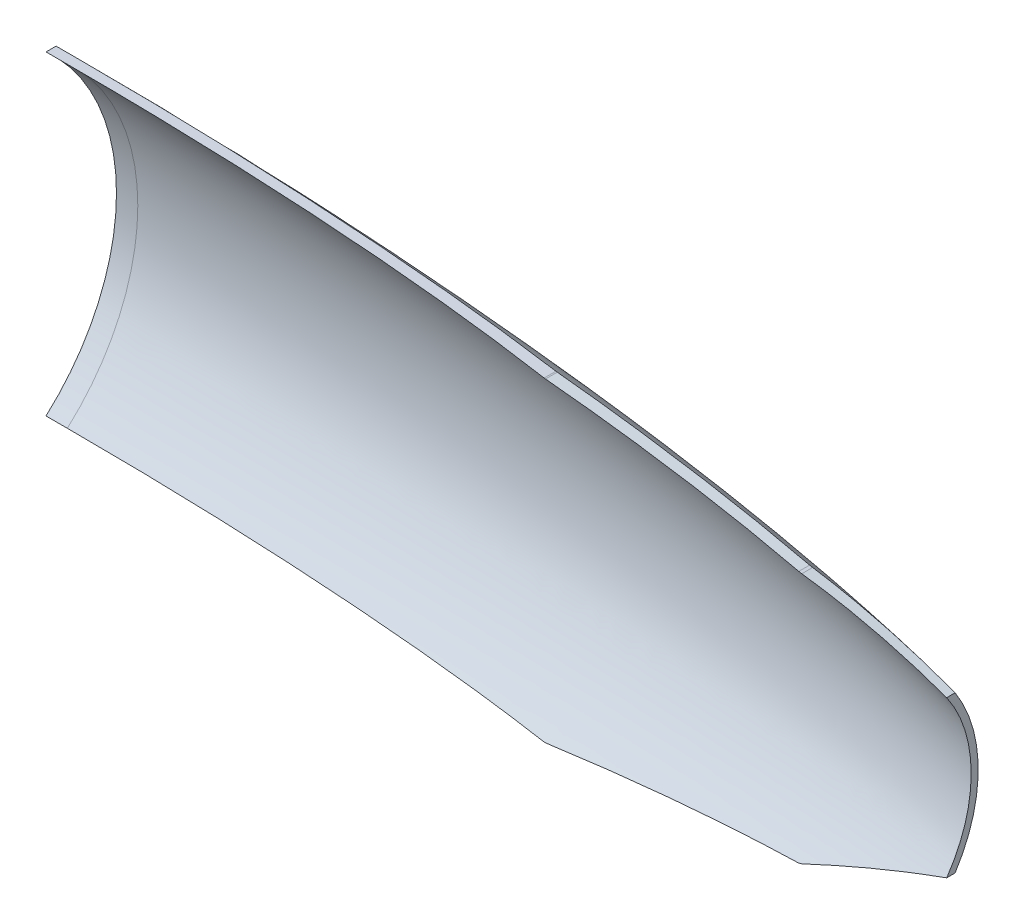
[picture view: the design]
ISO-10303-21;
HEADER;
FILE_DESCRIPTION(('STEP AP214'),'2;1');
FILE_NAME('part.step','',(''),(''),'','','');
FILE_SCHEMA(('AUTOMOTIVE_DESIGN { 1 0 10303 214 1 1 1 1 }'));
ENDSEC;
DATA;
#1=APPLICATION_CONTEXT('core data for automotive mechanical design processes');
#2=APPLICATION_PROTOCOL_DEFINITION('international standard','automotive_design',2000,#1);
#3=PRODUCT_CONTEXT('',#1,'mechanical');
#4=PRODUCT('Part','Part','',(#3));
#5=PRODUCT_RELATED_PRODUCT_CATEGORY('part','',(#4));
#6=PRODUCT_DEFINITION_FORMATION('','',#4);
#7=PRODUCT_DEFINITION_CONTEXT('part definition',#1,'design');
#8=PRODUCT_DEFINITION('design','',#6,#7);
#9=PRODUCT_DEFINITION_SHAPE('','',#8);
#10=(LENGTH_UNIT() NAMED_UNIT(*) SI_UNIT(.MILLI.,.METRE.));
#11=(NAMED_UNIT(*) PLANE_ANGLE_UNIT() SI_UNIT($,.RADIAN.));
#12=(NAMED_UNIT(*) SI_UNIT($,.STERADIAN.) SOLID_ANGLE_UNIT());
#13=UNCERTAINTY_MEASURE_WITH_UNIT(LENGTH_MEASURE(1.E-05),#10,'distance_accuracy_value','');
#14=(GEOMETRIC_REPRESENTATION_CONTEXT(3) GLOBAL_UNCERTAINTY_ASSIGNED_CONTEXT((#13)) GLOBAL_UNIT_ASSIGNED_CONTEXT((#10,
#11,#12)) REPRESENTATION_CONTEXT('',''));
#15=CARTESIAN_POINT('',(0.,0.,0.));
#16=DIRECTION('',(0.,0.,1.));
#17=DIRECTION('',(1.,0.,0.));
#18=AXIS2_PLACEMENT_3D('',#15,#16,#17);
#19=CARTESIAN_POINT('',(0.,0.,0.));
#20=DIRECTION('',(0.,0.,-1.));
#21=DIRECTION('',(1.,0.,0.));
#22=AXIS2_PLACEMENT_3D('',#19,#20,#21);
#23=ELLIPSE('',#22,558.8,101.346);
#24=TRIMMED_CURVE('',#23,(PARAMETER_VALUE(0.)),(PARAMETER_VALUE(3.14159265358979)),.T.,.PARAMETER.);
#25=CARTESIAN_POINT('',(0.,0.,0.));
#26=DIRECTION('',(-1.,0.,0.));
#27=AXIS1_PLACEMENT('',#25,#26);
#28=SURFACE_OF_REVOLUTION('',#24,#27);
#29=CARTESIAN_POINT('',(236.728,73.152,-55.4660351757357));
#30=CARTESIAN_POINT('',(234.412400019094,73.152,-55.7910992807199));
#31=CARTESIAN_POINT('',(232.095758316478,73.152,-56.1087081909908));
#32=CARTESIAN_POINT('',(227.460571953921,73.152,-56.7296548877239));
#33=CARTESIAN_POINT('',(225.14202730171,73.152,-57.0329927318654));
#34=CARTESIAN_POINT('',(220.503655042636,73.152,-57.6259805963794));
#35=CARTESIAN_POINT('',(218.183827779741,73.152,-57.9156333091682));
#36=CARTESIAN_POINT('',(213.54257951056,73.152,-58.481872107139));
#37=CARTESIAN_POINT('',(211.221158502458,73.152,-58.758458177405));
#38=CARTESIAN_POINT('',(204.255226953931,73.152,-59.5693361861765));
#39=CARTESIAN_POINT('',(199.608515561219,73.152,-60.0848157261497));
#40=CARTESIAN_POINT('',(190.31042102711,73.152,-61.0691190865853));
#41=CARTESIAN_POINT('',(185.659038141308,73.152,-61.5379453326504));
#42=CARTESIAN_POINT('',(176.352150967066,73.152,-62.4318897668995));
#43=CARTESIAN_POINT('',(171.696646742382,73.152,-62.8570086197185));
#44=CARTESIAN_POINT('',(162.382035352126,73.152,-63.6660000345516));
#45=CARTESIAN_POINT('',(157.722928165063,73.152,-64.0498723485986));
#46=CARTESIAN_POINT('',(148.408522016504,73.152,-64.7778904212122));
#47=CARTESIAN_POINT('',(143.753227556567,73.152,-65.1220938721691));
#48=CARTESIAN_POINT('',(134.439888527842,73.152,-65.7731646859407));
#49=CARTESIAN_POINT('',(129.781843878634,73.152,-66.0800308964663));
#50=CARTESIAN_POINT('',(120.46341448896,73.152,-66.6578793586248));
#51=CARTESIAN_POINT('',(115.803029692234,73.152,-66.928860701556));
#52=CARTESIAN_POINT('',(106.480317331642,73.152,-67.4361588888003));
#53=CARTESIAN_POINT('',(101.81798974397,73.152,-67.6724752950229));
#54=CARTESIAN_POINT('',(92.4917797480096,73.152,-68.1114620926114));
#55=CARTESIAN_POINT('',(87.8278973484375,73.152,-68.3141326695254));
#56=CARTESIAN_POINT('',(78.4989511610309,73.152,-68.6866720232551));
#57=CARTESIAN_POINT('',(73.8338874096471,73.152,-68.8565417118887));
#58=CARTESIAN_POINT('',(66.2881148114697,73.152,-69.1053097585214));
#59=CARTESIAN_POINT('',(63.4077294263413,73.152,-69.1941448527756));
#60=CARTESIAN_POINT('',(57.6466872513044,73.152,-69.3597080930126));
#61=CARTESIAN_POINT('',(54.7660304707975,73.152,-69.4364365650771));
#62=CARTESIAN_POINT('',(49.0044733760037,73.152,-69.577903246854));
#63=CARTESIAN_POINT('',(46.1235730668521,73.152,-69.6426416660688));
#64=CARTESIAN_POINT('',(40.361554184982,73.152,-69.7602247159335));
#65=CARTESIAN_POINT('',(37.4804356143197,73.152,-69.8130694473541));
#66=CARTESIAN_POINT('',(31.7162714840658,73.152,-69.9069713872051));
#67=CARTESIAN_POINT('',(28.8332258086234,73.152,-69.9480214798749));
#68=CARTESIAN_POINT('',(23.066964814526,73.152,-70.0183512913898));
#69=CARTESIAN_POINT('',(20.1837494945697,73.152,-70.0476309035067));
#70=CARTESIAN_POINT('',(14.4171729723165,73.152,-70.0944628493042));
#71=CARTESIAN_POINT('',(11.533811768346,73.152,-70.1120149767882));
#72=CARTESIAN_POINT('',(5.76696701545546,73.152,-70.1354131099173));
#73=CARTESIAN_POINT('',(2.88348346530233,73.152,-70.1412588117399));
#74=CARTESIAN_POINT('',(0.,73.152,-70.1412618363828));
#75=B_SPLINE_CURVE_WITH_KNOTS('',3,(#29,#30,#31,#32,#33,#34,#35,#36,#37,#38,#39,#40,#41,#42,#43,
#44,#45,#46,#47,#48,#49,#50,#51,#52,#53,#54,#55,#56,#57,#58,#59,#60,#61,#62,#63,#64,#65,#66,#67,
#68,#69,#70,#71,#72,#73,#74),.UNSPECIFIED.,.F.,.F.,(4,2,2,2,2,2,2,2,2,2,2,2,2,2,2,2,2,2,2,2,2,2,
4),(0.,7.01489550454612,14.0297626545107,21.0432439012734,28.0567331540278,42.0821018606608,
56.1067409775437,70.1311667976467,84.1556769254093,98.1595260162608,112.163807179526,
126.168442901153,140.173255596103,154.177991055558,168.182337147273,176.827579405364,
185.472588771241,194.117447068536,202.762232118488,211.41222170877,220.062289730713,
228.712509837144,237.362954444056),.UNSPECIFIED.);
#76=CARTESIAN_POINT('',(236.728,73.1520000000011,-55.4660351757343));
#77=VERTEX_POINT('',#76);
#78=CARTESIAN_POINT('',(0.,73.152,-70.1412618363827));
#79=VERTEX_POINT('',#78);
#80=EDGE_CURVE('E110',#77,#79,#75,.T.);
#81=ORIENTED_EDGE('',*,*,#80,.F.);
#82=CARTESIAN_POINT('',(237.39274838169,73.1171096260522,-55.4185672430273));
#83=CARTESIAN_POINT('',(237.281958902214,73.1229245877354,-55.4265054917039));
#84=CARTESIAN_POINT('',(237.171168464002,73.1287395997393,-55.4344302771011));
#85=CARTESIAN_POINT('',(236.949585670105,73.140369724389,-55.4502529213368));
#86=CARTESIAN_POINT('',(236.838793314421,73.1461848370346,-55.4581507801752));
#87=CARTESIAN_POINT('',(236.728,73.1520000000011,-55.4660351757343));
#88=B_SPLINE_CURVE_WITH_KNOTS('',3,(#82,#83,#84,#85,#86,#87),.UNSPECIFIED.,.F.,.F.,(4,2,4),(0.,
0.333676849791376,0.667353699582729),.UNSPECIFIED.);
#89=CARTESIAN_POINT('',(237.39274838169,73.117109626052,-55.4185672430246));
#90=VERTEX_POINT('',#89);
#91=EDGE_CURVE('E151',#90,#77,#88,.T.);
#92=ORIENTED_EDGE('',*,*,#91,.F.);
#93=CARTESIAN_POINT('',(358.97099166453,58.6193913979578,-50.9530256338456));
#94=CARTESIAN_POINT('',(357.286512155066,58.8202588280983,-51.1122840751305));
#95=CARTESIAN_POINT('',(355.601604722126,59.0211772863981,-51.2669071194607));
#96=CARTESIAN_POINT('',(352.230997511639,59.4231086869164,-51.5671001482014));
#97=CARTESIAN_POINT('',(350.545297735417,59.6241216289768,-51.712670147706));
#98=CARTESIAN_POINT('',(345.488612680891,60.2271110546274,-52.1360010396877));
#99=CARTESIAN_POINT('',(342.116527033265,60.629218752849,-52.4005256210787));
#100=CARTESIAN_POINT('',(335.371053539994,61.4335894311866,-52.8956513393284));
#101=CARTESIAN_POINT('',(331.997666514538,61.8358523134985,-53.1262638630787));
#102=CARTESIAN_POINT('',(325.249659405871,62.6405251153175,-53.5548307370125));
#103=CARTESIAN_POINT('',(321.875039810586,63.0429349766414,-53.7527928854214));
#104=CARTESIAN_POINT('',(315.124633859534,63.8478938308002,-54.1170930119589));
#105=CARTESIAN_POINT('',(311.748847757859,64.2504427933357,-54.2834357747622));
#106=CARTESIAN_POINT('',(304.99615945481,65.0556738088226,-54.5853284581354));
#107=CARTESIAN_POINT('',(301.619257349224,65.4583558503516,-54.7208805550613));
#108=CARTESIAN_POINT('',(294.864550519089,66.2638275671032,-54.9618375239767));
#109=CARTESIAN_POINT('',(291.486745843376,66.6666172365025,-55.0672437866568));
#110=CARTESIAN_POINT('',(284.730037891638,67.4723275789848,-55.248408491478));
#111=CARTESIAN_POINT('',(281.351134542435,67.8752482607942,-55.3241641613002));
#112=CARTESIAN_POINT('',(274.592231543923,68.6812203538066,-55.4463653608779));
#113=CARTESIAN_POINT('',(271.212231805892,69.0842717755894,-55.4928059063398));
#114=CARTESIAN_POINT('',(264.451137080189,69.8905052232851,-55.5565687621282));
#115=CARTESIAN_POINT('',(261.070042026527,70.2936872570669,-55.5738839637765));
#116=CARTESIAN_POINT('',(254.306756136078,71.1001819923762,-55.579458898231));
#117=CARTESIAN_POINT('',(250.924565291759,71.503494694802,-55.5677094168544));
#118=CARTESIAN_POINT('',(244.159087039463,72.3102508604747,-55.5150460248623));
#119=CARTESIAN_POINT('',(240.775799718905,72.7136943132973,-55.4741207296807));
#120=CARTESIAN_POINT('',(237.39274838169,73.117109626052,-55.4185672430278));
#121=B_SPLINE_CURVE_WITH_KNOTS('',3,(#93,#94,#95,#96,#97,#98,#99,#100,#101,#102,#103,#104,#105,
#106,#107,#108,#109,#110,#111,#112,#113,#114,#115,#116,#117,#118,#119,#120),.UNSPECIFIED.,.F.,
.F.,(4,2,2,2,2,2,2,2,2,2,2,2,2,4),(0.,5.11160406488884,10.2231996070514,20.4417947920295,
30.6569509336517,40.8696637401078,51.0808299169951,61.2912741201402,71.501247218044,
81.7121747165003,91.9248378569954,102.139993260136,112.358387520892,122.580771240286),.UNSPECIFIED.);
#122=CARTESIAN_POINT('',(358.97099166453,58.6193913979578,-50.9530256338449));
#123=VERTEX_POINT('',#122);
#124=EDGE_CURVE('E150',#123,#90,#121,.T.);
#125=ORIENTED_EDGE('',*,*,#124,.F.);
#126=CARTESIAN_POINT('',(360.290868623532,58.2986350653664,-51.0145733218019));
#127=CARTESIAN_POINT('',(360.070877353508,58.3520973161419,-51.0045828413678));
#128=CARTESIAN_POINT('',(359.850891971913,58.4055581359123,-50.9944586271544));
#129=CARTESIAN_POINT('',(359.410932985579,58.5124769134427,-50.9739427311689));
#130=CARTESIAN_POINT('',(359.19095938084,58.5659348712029,-50.9635510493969));
#131=CARTESIAN_POINT('',(358.97099166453,58.6193913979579,-50.9530256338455));
#132=B_SPLINE_CURVE_WITH_KNOTS('',3,(#126,#127,#128,#129,#130,#131),.UNSPECIFIED.,.F.,.F.,(4,2,
4),(0.,0.679843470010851,1.35968694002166),.UNSPECIFIED.);
#133=CARTESIAN_POINT('',(360.290868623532,58.2986350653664,-51.0145733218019));
#134=VERTEX_POINT('',#133);
#135=EDGE_CURVE('E155',#134,#123,#132,.T.);
#136=ORIENTED_EDGE('',*,*,#135,.F.);
#137=CARTESIAN_POINT('',(421.64,36.2129477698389,-55.7848384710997));
#138=CARTESIAN_POINT('',(419.925838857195,36.8300457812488,-55.8103963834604));
#139=CARTESIAN_POINT('',(418.21150821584,37.4472048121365,-55.823131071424));
#140=CARTESIAN_POINT('',(414.784668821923,38.6808669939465,-55.822929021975));
#141=CARTESIAN_POINT('',(413.072160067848,39.2973701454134,-55.8100195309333));
#142=CARTESIAN_POINT('',(409.648963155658,40.5297210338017,-55.7585807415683));
#143=CARTESIAN_POINT('',(407.938274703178,41.1455688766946,-55.7200735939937));
#144=CARTESIAN_POINT('',(404.518719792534,42.3766086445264,-55.6173620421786));
#145=CARTESIAN_POINT('',(402.809852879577,42.9918007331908,-55.553174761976));
#146=CARTESIAN_POINT('',(399.393945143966,44.2215275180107,-55.3989237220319));
#147=CARTESIAN_POINT('',(397.686903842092,44.8360623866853,-55.3088719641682));
#148=CARTESIAN_POINT('',(394.274654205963,46.0644722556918,-55.1025990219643));
#149=CARTESIAN_POINT('',(392.569445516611,46.6783473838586,-54.9863844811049));
#150=CARTESIAN_POINT('',(389.160609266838,47.9055284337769,-54.7273549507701));
#151=CARTESIAN_POINT('',(387.456981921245,48.5188342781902,-54.5845367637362));
#152=CARTESIAN_POINT('',(384.051597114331,49.7447728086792,-54.2717729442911));
#153=CARTESIAN_POINT('',(382.349840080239,50.3574053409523,-54.1018220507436));
#154=CARTESIAN_POINT('',(378.94826924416,51.5819708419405,-53.7341195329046));
#155=CARTESIAN_POINT('',(377.248456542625,52.1939034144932,-53.5363563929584));
#156=CARTESIAN_POINT('',(373.850865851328,53.4170360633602,-53.1122001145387));
#157=CARTESIAN_POINT('',(372.153089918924,54.0282353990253,-52.8857883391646));
#158=CARTESIAN_POINT('',(368.759676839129,55.2498641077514,-52.4033453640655));
#159=CARTESIAN_POINT('',(367.064043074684,55.8602922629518,-52.1472872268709));
#160=CARTESIAN_POINT('',(363.675062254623,57.0803253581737,-51.6043152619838));
#161=CARTESIAN_POINT('',(361.98172043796,57.6899284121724,-51.3173645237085));
#162=CARTESIAN_POINT('',(360.290868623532,58.2986350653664,-51.0145733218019));
#163=B_SPLINE_CURVE_WITH_KNOTS('',3,(#137,#138,#139,#140,#141,#142,#143,#144,#145,#146,#147,
#148,#149,#150,#151,#152,#153,#154,#155,#156,#157,#158,#159,#160,#161,#162),.UNSPECIFIED.,.F.,
.F.,(4,2,2,2,2,2,2,2,2,2,2,2,4),(0.,5.46606021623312,10.9263159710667,16.3818528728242,
21.8337579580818,27.2831372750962,32.7311343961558,38.1797867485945,43.6294969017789,
49.0814701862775,54.5370085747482,59.9975434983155,65.4646766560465),.UNSPECIFIED.);
#164=CARTESIAN_POINT('',(421.64,36.2129477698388,-55.7848384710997));
#165=VERTEX_POINT('',#164);
#166=EDGE_CURVE('E159',#165,#134,#163,.T.);
#167=ORIENTED_EDGE('',*,*,#166,.F.);
#168=CARTESIAN_POINT('',(421.64,0.,0.));
#169=DIRECTION('',(-1.,0.,0.));
#170=DIRECTION('',(0.,0.,1.));
#171=AXIS2_PLACEMENT_3D('',#168,#169,#170);
#172=CIRCLE('',#171,66.508088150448);
#173=CARTESIAN_POINT('',(421.64,-36.2129477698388,-55.7848384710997));
#174=VERTEX_POINT('',#173);
#175=EDGE_CURVE('E142',#174,#165,#172,.F.);
#176=ORIENTED_EDGE('',*,*,#175,.F.);
#177=CARTESIAN_POINT('',(360.290868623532,-58.2986350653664,-51.0145733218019));
#178=CARTESIAN_POINT('',(361.98172043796,-57.6899284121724,-51.3173645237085));
#179=CARTESIAN_POINT('',(363.675062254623,-57.0803253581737,-51.6043152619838));
#180=CARTESIAN_POINT('',(367.064043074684,-55.8602922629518,-52.1472872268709));
#181=CARTESIAN_POINT('',(368.759676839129,-55.2498641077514,-52.4033453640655));
#182=CARTESIAN_POINT('',(372.153089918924,-54.0282353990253,-52.8857883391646));
#183=CARTESIAN_POINT('',(373.850865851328,-53.4170360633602,-53.1122001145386));
#184=CARTESIAN_POINT('',(377.248456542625,-52.1939034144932,-53.5363563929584));
#185=CARTESIAN_POINT('',(378.94826924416,-51.5819708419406,-53.7341195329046));
#186=CARTESIAN_POINT('',(382.349840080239,-50.3574053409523,-54.1018220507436));
#187=CARTESIAN_POINT('',(384.051597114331,-49.7447728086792,-54.2717729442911));
#188=CARTESIAN_POINT('',(387.456981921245,-48.5188342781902,-54.5845367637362));
#189=CARTESIAN_POINT('',(389.160609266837,-47.9055284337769,-54.7273549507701));
#190=CARTESIAN_POINT('',(392.569445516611,-46.6783473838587,-54.9863844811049));
#191=CARTESIAN_POINT('',(394.274654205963,-46.0644722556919,-55.1025990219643));
#192=CARTESIAN_POINT('',(397.686903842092,-44.8360623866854,-55.3088719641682));
#193=CARTESIAN_POINT('',(399.393945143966,-44.2215275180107,-55.398923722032));
#194=CARTESIAN_POINT('',(402.809852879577,-42.9918007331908,-55.553174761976));
#195=CARTESIAN_POINT('',(404.518719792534,-42.3766086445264,-55.6173620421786));
#196=CARTESIAN_POINT('',(407.938274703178,-41.1455688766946,-55.7200735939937));
#197=CARTESIAN_POINT('',(409.648963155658,-40.5297210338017,-55.7585807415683));
#198=CARTESIAN_POINT('',(413.072160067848,-39.2973701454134,-55.8100195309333));
#199=CARTESIAN_POINT('',(414.784668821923,-38.6808669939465,-55.822929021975));
#200=CARTESIAN_POINT('',(418.21150821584,-37.4472048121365,-55.823131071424));
#201=CARTESIAN_POINT('',(419.925838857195,-36.8300457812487,-55.8103963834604));
#202=CARTESIAN_POINT('',(421.64,-36.2129477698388,-55.7848384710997));
#203=B_SPLINE_CURVE_WITH_KNOTS('',3,(#177,#178,#179,#180,#181,#182,#183,#184,#185,#186,#187,
#188,#189,#190,#191,#192,#193,#194,#195,#196,#197,#198,#199,#200,#201,#202),.UNSPECIFIED.,.F.,
.F.,(4,2,2,2,2,2,2,2,2,2,2,2,4),(0.,5.46713315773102,10.9276680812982,16.3832064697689,
21.8351797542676,27.284889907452,32.7335422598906,38.1815393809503,43.6309186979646,
49.0828237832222,54.5383606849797,59.9986164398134,65.4646766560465),.UNSPECIFIED.);
#204=CARTESIAN_POINT('',(360.290868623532,-58.2986350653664,-51.0145733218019));
#205=VERTEX_POINT('',#204);
#206=EDGE_CURVE('E164',#205,#174,#203,.T.);
#207=ORIENTED_EDGE('',*,*,#206,.F.);
#208=CARTESIAN_POINT('',(358.97099166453,-58.6193913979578,-50.9530256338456));
#209=CARTESIAN_POINT('',(359.190959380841,-58.5659348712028,-50.9635510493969));
#210=CARTESIAN_POINT('',(359.410932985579,-58.5124769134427,-50.9739427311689));
#211=CARTESIAN_POINT('',(359.850891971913,-58.4055581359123,-50.9944586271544));
#212=CARTESIAN_POINT('',(360.070877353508,-58.3520973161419,-51.0045828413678));
#213=CARTESIAN_POINT('',(360.290868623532,-58.2986350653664,-51.0145733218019));
#214=B_SPLINE_CURVE_WITH_KNOTS('',3,(#208,#209,#210,#211,#212,#213),.UNSPECIFIED.,.F.,.F.,(4,2,
4),(0.,0.679843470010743,1.35968694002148),.UNSPECIFIED.);
#215=CARTESIAN_POINT('',(358.97099166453,-58.6193913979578,-50.9530256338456));
#216=VERTEX_POINT('',#215);
#217=EDGE_CURVE('E168',#216,#205,#214,.T.);
#218=ORIENTED_EDGE('',*,*,#217,.F.);
#219=CARTESIAN_POINT('',(237.39274838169,-73.1171096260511,-55.4185672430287));
#220=CARTESIAN_POINT('',(240.775799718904,-72.7136943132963,-55.474120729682));
#221=CARTESIAN_POINT('',(244.159087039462,-72.3102508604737,-55.5150460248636));
#222=CARTESIAN_POINT('',(250.924565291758,-71.503494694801,-55.5677094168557));
#223=CARTESIAN_POINT('',(254.306756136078,-71.1001819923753,-55.5794588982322));
#224=CARTESIAN_POINT('',(261.070042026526,-70.293687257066,-55.5738839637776));
#225=CARTESIAN_POINT('',(264.451137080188,-69.8905052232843,-55.5565687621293));
#226=CARTESIAN_POINT('',(271.212231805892,-69.0842717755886,-55.4928059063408));
#227=CARTESIAN_POINT('',(274.592231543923,-68.6812203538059,-55.4463653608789));
#228=CARTESIAN_POINT('',(281.351134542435,-67.8752482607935,-55.3241641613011));
#229=CARTESIAN_POINT('',(284.730037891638,-67.4723275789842,-55.2484084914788));
#230=CARTESIAN_POINT('',(291.486745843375,-66.6666172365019,-55.0672437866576));
#231=CARTESIAN_POINT('',(294.864550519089,-66.2638275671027,-54.9618375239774));
#232=CARTESIAN_POINT('',(301.619257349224,-65.4583558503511,-54.7208805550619));
#233=CARTESIAN_POINT('',(304.99615945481,-65.0556738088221,-54.585328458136));
#234=CARTESIAN_POINT('',(311.748847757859,-64.2504427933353,-54.2834357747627));
#235=CARTESIAN_POINT('',(315.124633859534,-63.8478938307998,-54.1170930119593));
#236=CARTESIAN_POINT('',(321.875039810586,-63.0429349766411,-53.7527928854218));
#237=CARTESIAN_POINT('',(325.249659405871,-62.6405251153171,-53.5548307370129));
#238=CARTESIAN_POINT('',(331.997666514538,-61.8358523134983,-53.126263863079));
#239=CARTESIAN_POINT('',(335.371053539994,-61.4335894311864,-52.8956513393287));
#240=CARTESIAN_POINT('',(342.116527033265,-60.6292187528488,-52.4005256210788));
#241=CARTESIAN_POINT('',(345.488612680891,-60.2271110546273,-52.1360010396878));
#242=CARTESIAN_POINT('',(350.545297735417,-59.6241216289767,-51.712670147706));
#243=CARTESIAN_POINT('',(352.230997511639,-59.4231086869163,-51.5671001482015));
#244=CARTESIAN_POINT('',(355.601604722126,-59.021177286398,-51.2669071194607));
#245=CARTESIAN_POINT('',(357.286512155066,-58.8202588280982,-51.1122840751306));
#246=CARTESIAN_POINT('',(358.97099166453,-58.6193913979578,-50.9530256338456));
#247=B_SPLINE_CURVE_WITH_KNOTS('',3,(#219,#220,#221,#222,#223,#224,#225,#226,#227,#228,#229,
#230,#231,#232,#233,#234,#235,#236,#237,#238,#239,#240,#241,#242,#243,#244,#245,#246),
.UNSPECIFIED.,.F.,.F.,(4,2,2,2,2,2,2,2,2,2,2,2,2,4),(0.,10.2223837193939,20.4407779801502,
30.6559333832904,40.8685965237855,51.0795240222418,61.2894971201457,71.4999413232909,
81.7111075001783,91.9238203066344,102.138976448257,112.357571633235,117.469167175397,
122.580771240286),.UNSPECIFIED.);
#248=CARTESIAN_POINT('',(237.39274838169,-73.1171096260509,-55.4185672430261));
#249=VERTEX_POINT('',#248);
#250=EDGE_CURVE('E172',#249,#216,#247,.T.);
#251=ORIENTED_EDGE('',*,*,#250,.F.);
#252=CARTESIAN_POINT('',(236.728,-73.1520000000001,-55.4660351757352));
#253=CARTESIAN_POINT('',(236.838793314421,-73.1461848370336,-55.4581507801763));
#254=CARTESIAN_POINT('',(236.949585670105,-73.140369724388,-55.4502529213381));
#255=CARTESIAN_POINT('',(237.171168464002,-73.1287395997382,-55.4344302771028));
#256=CARTESIAN_POINT('',(237.281958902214,-73.1229245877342,-55.4265054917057));
#257=CARTESIAN_POINT('',(237.39274838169,-73.1171096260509,-55.4185672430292));
#258=B_SPLINE_CURVE_WITH_KNOTS('',3,(#252,#253,#254,#255,#256,#257),.UNSPECIFIED.,.F.,.F.,(4,2,
4),(0.,0.333676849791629,0.667353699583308),.UNSPECIFIED.);
#259=CARTESIAN_POINT('',(236.728,-73.152,-55.4660351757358));
#260=VERTEX_POINT('',#259);
#261=EDGE_CURVE('E82',#260,#249,#258,.T.);
#262=ORIENTED_EDGE('',*,*,#261,.F.);
#263=CARTESIAN_POINT('',(0.,-73.152,-70.1412618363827));
#264=CARTESIAN_POINT('',(5.55624053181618,-73.152,-70.1412197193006));
#265=CARTESIAN_POINT('',(11.1124833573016,-73.152,-70.1195441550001));
#266=CARTESIAN_POINT('',(22.2261068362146,-73.152,-70.0326138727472));
#267=CARTESIAN_POINT('',(27.7834873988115,-73.152,-69.9673475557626));
#268=CARTESIAN_POINT('',(38.8986828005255,-73.152,-69.7929056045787));
#269=CARTESIAN_POINT('',(44.4564975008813,-73.152,-69.6837211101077));
#270=CARTESIAN_POINT('',(55.5718501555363,-73.152,-69.4208160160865));
#271=CARTESIAN_POINT('',(61.1293879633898,-73.152,-69.2670892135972));
#272=CARTESIAN_POINT('',(72.2434704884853,-73.152,-68.9142386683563));
#273=CARTESIAN_POINT('',(77.8000150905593,-73.152,-68.7151112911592));
#274=CARTESIAN_POINT('',(88.911388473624,-73.152,-68.2703180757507));
#275=CARTESIAN_POINT('',(94.4662172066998,-73.152,-68.0246510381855));
#276=CARTESIAN_POINT('',(105.560709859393,-73.152,-67.4859441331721));
#277=CARTESIAN_POINT('',(111.10037914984,-73.152,-67.193015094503));
#278=CARTESIAN_POINT('',(122.176647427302,-73.152,-66.5575816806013));
#279=CARTESIAN_POINT('',(127.713246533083,-73.152,-66.2150793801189));
#280=CARTESIAN_POINT('',(138.782647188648,-73.152,-65.4782765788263));
#281=CARTESIAN_POINT('',(144.315448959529,-73.152,-65.0839794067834));
#282=CARTESIAN_POINT('',(155.376492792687,-73.152,-64.2408592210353));
#283=CARTESIAN_POINT('',(160.904735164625,-73.152,-63.7920402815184));
#284=CARTESIAN_POINT('',(171.955841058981,-73.152,-62.8365263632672));
#285=CARTESIAN_POINT('',(177.47870492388,-73.152,-62.3298353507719));
#286=CARTESIAN_POINT('',(188.518217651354,-73.152,-61.2544550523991));
#287=CARTESIAN_POINT('',(194.034866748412,-73.152,-60.6857681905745));
#288=CARTESIAN_POINT('',(201.099395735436,-73.152,-59.9140130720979));
#289=CARTESIAN_POINT('',(202.6506836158,-73.152,-59.7418537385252));
#290=CARTESIAN_POINT('',(205.75264240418,-73.152,-59.3920784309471));
#291=CARTESIAN_POINT('',(207.303313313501,-73.152,-59.2144624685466));
#292=CARTESIAN_POINT('',(210.403999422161,-73.152,-58.8536363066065));
#293=CARTESIAN_POINT('',(211.954014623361,-73.152,-58.6704261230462));
#294=CARTESIAN_POINT('',(215.053351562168,-73.152,-58.2982616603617));
#295=CARTESIAN_POINT('',(216.602673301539,-73.152,-58.1093073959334));
#296=CARTESIAN_POINT('',(219.701237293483,-73.152,-57.7254143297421));
#297=CARTESIAN_POINT('',(221.250479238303,-73.152,-57.5304730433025));
#298=CARTESIAN_POINT('',(224.348189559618,-73.152,-57.1345102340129));
#299=CARTESIAN_POINT('',(225.896657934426,-73.152,-56.9334886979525));
#300=CARTESIAN_POINT('',(228.992779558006,-73.152,-56.5251823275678));
#301=CARTESIAN_POINT('',(230.540432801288,-73.152,-56.3178974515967));
#302=CARTESIAN_POINT('',(233.634879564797,-73.152,-55.8968636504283));
#303=CARTESIAN_POINT('',(235.181673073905,-73.152,-55.6831146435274));
#304=CARTESIAN_POINT('',(236.728,-73.152,-55.4660351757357));
#305=B_SPLINE_CURVE_WITH_KNOTS('',3,(#263,#264,#265,#266,#267,#268,#269,#270,#271,#272,#273,
#274,#275,#276,#277,#278,#279,#280,#281,#282,#283,#284,#285,#286,#287,#288,#289,#290,#291,#292,
#293,#294,#295,#296,#297,#298,#299,#300,#301,#302,#303,#304),.UNSPECIFIED.,.F.,.F.,(4,2,2,2,2,2,
2,2,2,2,2,2,2,2,2,2,2,2,2,2,4),(0.,16.668683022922,33.3418031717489,50.0182887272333,
66.6970977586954,83.3772424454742,100.057817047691,116.699829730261,133.341146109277,
149.981393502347,166.620398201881,183.258263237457,199.895477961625,204.577906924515,
209.260325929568,213.942731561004,218.625125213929,223.309489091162,227.993863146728,
232.67826835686,237.362732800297),.UNSPECIFIED.);
#306=CARTESIAN_POINT('',(0.,-73.152,-70.1412618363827));
#307=VERTEX_POINT('',#306);
#308=EDGE_CURVE('E123',#307,#260,#305,.T.);
#309=ORIENTED_EDGE('',*,*,#308,.F.);
#310=CARTESIAN_POINT('',(0.,0.,0.));
#311=DIRECTION('',(-1.,0.,0.));
#312=DIRECTION('',(0.,0.,1.));
#313=AXIS2_PLACEMENT_3D('',#310,#311,#312);
#314=CIRCLE('',#313,101.346);
#315=EDGE_CURVE('E127',#79,#307,#314,.T.);
#316=ORIENTED_EDGE('',*,*,#315,.F.);
#317=EDGE_LOOP('',(#81,#92,#125,#136,#167,#176,#207,#218,#251,#262,#309,#316));
#318=FACE_BOUND('',#317,.T.);
#319=ADVANCED_FACE('F38',(#318),#28,.T.);
#320=CARTESIAN_POINT('',(-9.906,0.,0.));
#321=DIRECTION('',(1.,0.,0.));
#322=DIRECTION('',(0.,0.,-1.));
#323=AXIS2_PLACEMENT_3D('',#320,#321,#322);
#324=CYLINDRICAL_SURFACE('',#323,101.346);
#325=DIRECTION('',(1.,0.,0.));
#326=VECTOR('',#325,1.);
#327=CARTESIAN_POINT('',(-9.906,73.152,-70.1412618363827));
#328=LINE('',#327,#326);
#329=CARTESIAN_POINT('',(-9.906,73.152,-70.1412618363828));
#330=VERTEX_POINT('',#329);
#331=EDGE_CURVE('E106',#79,#330,#328,.F.);
#332=ORIENTED_EDGE('',*,*,#331,.F.);
#333=ORIENTED_EDGE('',*,*,#315,.T.);
#334=DIRECTION('',(1.,0.,0.));
#335=VECTOR('',#334,1.);
#336=CARTESIAN_POINT('',(-9.906,-73.152,-70.1412618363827));
#337=LINE('',#336,#335);
#338=CARTESIAN_POINT('',(-9.906,-73.152,-70.1412618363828));
#339=VERTEX_POINT('',#338);
#340=EDGE_CURVE('E12',#339,#307,#337,.T.);
#341=ORIENTED_EDGE('',*,*,#340,.F.);
#342=CARTESIAN_POINT('',(-9.906,0.,0.));
#343=DIRECTION('',(-1.,0.,0.));
#344=DIRECTION('',(0.,0.,1.));
#345=AXIS2_PLACEMENT_3D('',#342,#343,#344);
#346=CIRCLE('',#345,101.346);
#347=EDGE_CURVE('E120',#330,#339,#346,.T.);
#348=ORIENTED_EDGE('',*,*,#347,.F.);
#349=EDGE_LOOP('',(#332,#333,#341,#348));
#350=FACE_BOUND('',#349,.T.);
#351=ADVANCED_FACE('F125',(#350),#324,.T.);
#352=CARTESIAN_POINT('',(-9.906,0.,0.));
#353=DIRECTION('',(-1.,0.,0.));
#354=DIRECTION('',(0.,0.,1.));
#355=AXIS2_PLACEMENT_3D('',#352,#353,#354);
#356=PLANE('',#355);
#357=CARTESIAN_POINT('',(-9.906,0.,0.));
#358=DIRECTION('',(-1.,0.,0.));
#359=DIRECTION('',(0.,0.,1.));
#360=AXIS2_PLACEMENT_3D('',#357,#358,#359);
#361=CIRCLE('',#360,98.171);
#362=CARTESIAN_POINT('',(-9.906,73.152,-65.4700705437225));
#363=VERTEX_POINT('',#362);
#364=CARTESIAN_POINT('',(-9.906,-73.152,-65.4700705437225));
#365=VERTEX_POINT('',#364);
#366=EDGE_CURVE('E122',#363,#365,#361,.T.);
#367=ORIENTED_EDGE('',*,*,#366,.F.);
#368=DIRECTION('',(0.,0.,1.));
#369=VECTOR('',#368,1.);
#370=CARTESIAN_POINT('',(-9.906,73.152,-101.346));
#371=LINE('',#370,#369);
#372=EDGE_CURVE('E103',#330,#363,#371,.T.);
#373=ORIENTED_EDGE('',*,*,#372,.F.);
#374=ORIENTED_EDGE('',*,*,#347,.T.);
#375=DIRECTION('',(0.,0.,1.));
#376=VECTOR('',#375,1.);
#377=CARTESIAN_POINT('',(-9.906,-73.152,-101.346));
#378=LINE('',#377,#376);
#379=EDGE_CURVE('E126',#339,#365,#378,.T.);
#380=ORIENTED_EDGE('',*,*,#379,.T.);
#381=EDGE_LOOP('',(#367,#373,#374,#380));
#382=FACE_BOUND('',#381,.T.);
#383=ADVANCED_FACE('F118',(#382),#356,.T.);
#384=CARTESIAN_POINT('',(0.,0.,0.));
#385=DIRECTION('',(0.,0.,-1.));
#386=DIRECTION('',(1.,0.,0.));
#387=AXIS2_PLACEMENT_3D('',#384,#385,#386);
#388=ELLIPSE('',#387,558.8,101.346);
#389=TRIMMED_CURVE('',#388,(PARAMETER_VALUE(0.)),(PARAMETER_VALUE(3.14159265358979)),.T.,.PARAMETER.);
#390=CARTESIAN_POINT('',(0.,0.,0.));
#391=DIRECTION('',(-1.,0.,0.));
#392=AXIS1_PLACEMENT('',#390,#391);
#393=SURFACE_OF_REVOLUTION('',#389,#392);
#394=OFFSET_SURFACE('',#393,-3.175,.F.);
#395=CARTESIAN_POINT('',(237.39274838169,73.117109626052,-49.9667395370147));
#396=CARTESIAN_POINT('',(237.28195913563,73.122924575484,-49.9749657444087));
#397=CARTESIAN_POINT('',(237.171168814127,73.1287395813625,-49.9831773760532));
#398=CARTESIAN_POINT('',(236.94958602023,73.1403697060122,-49.9995714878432));
#399=CARTESIAN_POINT('',(236.838793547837,73.1461848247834,-50.0077539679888));
#400=CARTESIAN_POINT('',(236.728,73.1520000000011,-50.0159218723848));
#401=B_SPLINE_CURVE_WITH_KNOTS('',3,(#395,#396,#397,#398,#399,#400),.UNSPECIFIED.,.F.,.F.,(4,2,
4),(0.,0.333738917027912,0.667477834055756),.UNSPECIFIED.);
#402=CARTESIAN_POINT('',(237.39274838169,73.117109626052,-49.9667395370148));
#403=VERTEX_POINT('',#402);
#404=CARTESIAN_POINT('',(236.728,73.1520000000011,-50.0159218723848));
#405=VERTEX_POINT('',#404);
#406=EDGE_CURVE('E129',#403,#405,#401,.T.);
#407=ORIENTED_EDGE('',*,*,#406,.T.);
#408=CARTESIAN_POINT('',(236.728,73.152,-50.0159218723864));
#409=CARTESIAN_POINT('',(234.503116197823,73.152,-50.3507222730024));
#410=CARTESIAN_POINT('',(232.277059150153,73.152,-50.6776850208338));
#411=CARTESIAN_POINT('',(227.822815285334,73.152,-51.3166867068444));
#412=CARTESIAN_POINT('',(225.594628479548,73.152,-51.6287257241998));
#413=CARTESIAN_POINT('',(221.136872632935,73.152,-52.2385591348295));
#414=CARTESIAN_POINT('',(218.907304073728,73.152,-52.536357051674));
#415=CARTESIAN_POINT('',(214.446403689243,73.152,-53.1184391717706));
#416=CARTESIAN_POINT('',(212.21507186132,73.152,-53.4027233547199));
#417=CARTESIAN_POINT('',(205.519296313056,73.152,-54.2361297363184));
#418=CARTESIAN_POINT('',(201.052431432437,73.152,-54.7658931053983));
#419=CARTESIAN_POINT('',(192.113636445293,73.152,-55.7778102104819));
#420=CARTESIAN_POINT('',(187.641706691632,73.152,-56.2599670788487));
#421=CARTESIAN_POINT('',(178.693393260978,73.152,-57.1800111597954));
#422=CARTESIAN_POINT('',(174.21700967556,73.152,-57.617899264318));
#423=CARTESIAN_POINT('',(165.260356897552,73.152,-58.4521716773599));
#424=CARTESIAN_POINT('',(160.780087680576,73.152,-58.8485557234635));
#425=CARTESIAN_POINT('',(151.823441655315,73.152,-59.6015106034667));
#426=CARTESIAN_POINT('',(147.347070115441,73.152,-59.9581442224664));
#427=CARTESIAN_POINT('',(138.391353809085,73.152,-60.6342601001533));
#428=CARTESIAN_POINT('',(133.912008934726,73.152,-60.9537409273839));
#429=CARTESIAN_POINT('',(124.950782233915,73.152,-61.5571599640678));
#430=CARTESIAN_POINT('',(120.468900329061,73.152,-61.8410970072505));
#431=CARTESIAN_POINT('',(111.503020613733,73.152,-62.3747792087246));
#432=CARTESIAN_POINT('',(107.019022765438,73.152,-62.6245237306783));
#433=CARTESIAN_POINT('',(98.0493204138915,73.152,-63.0909519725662));
#434=CARTESIAN_POINT('',(93.5636159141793,73.152,-63.3076357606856));
#435=CARTESIAN_POINT('',(84.5908945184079,73.152,-63.7088855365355));
#436=CARTESIAN_POINT('',(80.1038776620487,73.152,-63.8934524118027));
#437=CARTESIAN_POINT('',(72.4681469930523,73.152,-64.1808369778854));
#438=CARTESIAN_POINT('',(69.3197299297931,73.152,-64.2916119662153));
#439=CARTESIAN_POINT('',(63.022500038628,73.152,-64.4979593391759));
#440=CARTESIAN_POINT('',(59.8736872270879,73.152,-64.5935322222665));
#441=CARTESIAN_POINT('',(53.5757087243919,73.152,-64.7696683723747));
#442=CARTESIAN_POINT('',(50.4265430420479,73.152,-64.8502319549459));
#443=CARTESIAN_POINT('',(44.1278986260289,73.152,-64.9965086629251));
#444=CARTESIAN_POINT('',(40.9784198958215,73.152,-65.0622219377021));
#445=CARTESIAN_POINT('',(34.6768486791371,73.152,-65.1789695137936));
#446=CARTESIAN_POINT('',(31.524755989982,73.152,-65.2299928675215));
#447=CARTESIAN_POINT('',(25.2203332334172,73.152,-65.317393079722));
#448=CARTESIAN_POINT('',(22.0680031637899,73.152,-65.3537697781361));
#449=CARTESIAN_POINT('',(15.7631427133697,73.152,-65.4119471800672));
#450=CARTESIAN_POINT('',(12.6106123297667,73.152,-65.4337475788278));
#451=CARTESIAN_POINT('',(6.30538791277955,73.152,-65.4628070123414));
#452=CARTESIAN_POINT('',(3.15269387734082,73.152,-65.470065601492));
#453=CARTESIAN_POINT('',(0.,73.152,-65.4700705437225));
#454=B_SPLINE_CURVE_WITH_KNOTS('',3,(#408,#409,#410,#411,#412,#413,#414,#415,#416,#417,#418,
#419,#420,#421,#422,#423,#424,#425,#426,#427,#428,#429,#430,#431,#432,#433,#434,#435,#436,#437,
#438,#439,#440,#441,#442,#443,#444,#445,#446,#447,#448,#449,#450,#451,#452,#453),.UNSPECIFIED.,
.F.,.F.,(4,2,2,2,2,2,2,2,2,2,2,2,2,2,2,2,2,2,2,2,2,2,4),(0.,6.74977644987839,13.4995170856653,
20.2475789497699,26.9956509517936,40.4898540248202,53.9831686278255,67.4762113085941,
80.9693392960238,94.4408437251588,107.91286702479,121.385332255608,134.85804818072,
148.330736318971,161.803052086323,171.254113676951,180.704865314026,190.155418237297,
199.605876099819,209.063358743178,218.520944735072,227.978728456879,237.436801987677),.UNSPECIFIED.);
#455=CARTESIAN_POINT('',(0.,73.152,-65.4700705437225));
#456=VERTEX_POINT('',#455);
#457=EDGE_CURVE('E138',#405,#456,#454,.T.);
#458=ORIENTED_EDGE('',*,*,#457,.T.);
#459=CARTESIAN_POINT('',(0.,0.,0.));
#460=DIRECTION('',(1.,0.,0.));
#461=DIRECTION('',(0.,0.,-1.));
#462=AXIS2_PLACEMENT_3D('',#459,#460,#461);
#463=CIRCLE('',#462,98.171);
#464=CARTESIAN_POINT('',(0.,-73.152,-65.4700705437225));
#465=VERTEX_POINT('',#464);
#466=EDGE_CURVE('E134',#456,#465,#463,.F.);
#467=ORIENTED_EDGE('',*,*,#466,.T.);
#468=CARTESIAN_POINT('',(0.,-73.152,-65.4700705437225));
#469=CARTESIAN_POINT('',(5.38005689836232,-73.152,-65.4700282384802));
#470=CARTESIAN_POINT('',(10.7601161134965,-73.152,-65.4489170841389));
#471=CARTESIAN_POINT('',(21.5214046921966,-73.152,-65.3642432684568));
#472=CARTESIAN_POINT('',(26.9026339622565,-73.152,-65.3006687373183));
#473=CARTESIAN_POINT('',(37.6655596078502,-73.152,-65.130736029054));
#474=CARTESIAN_POINT('',(43.0472558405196,-73.152,-65.024368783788));
#475=CARTESIAN_POINT('',(53.810404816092,-73.152,-64.7682203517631));
#476=CARTESIAN_POINT('',(59.1918574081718,-73.152,-64.6184328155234));
#477=CARTESIAN_POINT('',(69.953803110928,-73.152,-64.2745774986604));
#478=CARTESIAN_POINT('',(75.3342961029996,-73.152,-64.0805059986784));
#479=CARTESIAN_POINT('',(86.0936001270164,-73.152,-63.646932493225));
#480=CARTESIAN_POINT('',(91.4724111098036,-73.152,-63.407429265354));
#481=CARTESIAN_POINT('',(102.214108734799,-73.152,-62.8821872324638));
#482=CARTESIAN_POINT('',(107.577001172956,-73.152,-62.5965672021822));
#483=CARTESIAN_POINT('',(118.299755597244,-73.152,-61.9768412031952));
#484=CARTESIAN_POINT('',(123.659617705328,-73.152,-61.6427373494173));
#485=CARTESIAN_POINT('',(134.37558600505,-73.152,-60.9237889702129));
#486=CARTESIAN_POINT('',(139.731692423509,-73.152,-60.538947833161));
#487=CARTESIAN_POINT('',(150.439387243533,-73.152,-59.7157483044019));
#488=CARTESIAN_POINT('',(155.790975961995,-73.152,-59.2773940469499));
#489=CARTESIAN_POINT('',(166.488814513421,-73.152,-58.3437424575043));
#490=CARTESIAN_POINT('',(171.835064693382,-73.152,-57.8484491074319));
#491=CARTESIAN_POINT('',(182.521382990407,-73.152,-56.7966836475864));
#492=CARTESIAN_POINT('',(187.861451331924,-73.152,-56.24021383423));
#493=CARTESIAN_POINT('',(195.015252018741,-73.152,-55.4496526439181));
#494=CARTESIAN_POINT('',(196.83225960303,-73.152,-55.2449525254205));
#495=CARTESIAN_POINT('',(200.465356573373,-73.152,-54.8275852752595));
#496=CARTESIAN_POINT('',(202.281445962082,-73.152,-54.6149181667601));
#497=CARTESIAN_POINT('',(205.912633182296,-73.152,-54.1813568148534));
#498=CARTESIAN_POINT('',(207.727731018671,-73.152,-53.9604626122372));
#499=CARTESIAN_POINT('',(211.356861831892,-73.152,-53.5101600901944));
#500=CARTESIAN_POINT('',(213.170894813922,-73.152,-53.2807518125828));
#501=CARTESIAN_POINT('',(216.798835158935,-73.152,-52.8129786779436));
#502=CARTESIAN_POINT('',(218.612741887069,-73.152,-52.574608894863));
#503=CARTESIAN_POINT('',(222.23933297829,-73.152,-52.0886917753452));
#504=CARTESIAN_POINT('',(224.052017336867,-73.152,-51.8411444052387));
#505=CARTESIAN_POINT('',(227.676080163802,-73.152,-51.336500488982));
#506=CARTESIAN_POINT('',(229.487458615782,-73.152,-51.0794038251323));
#507=CARTESIAN_POINT('',(233.10881748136,-73.152,-50.5552419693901));
#508=CARTESIAN_POINT('',(234.918797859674,-73.152,-50.2881765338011));
#509=CARTESIAN_POINT('',(236.728,-73.152,-50.0159218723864));
#510=B_SPLINE_CURVE_WITH_KNOTS('',3,(#468,#469,#470,#471,#472,#473,#474,#475,#476,#477,#478,
#479,#480,#481,#482,#483,#484,#485,#486,#487,#488,#489,#490,#491,#492,#493,#494,#495,#496,#497,
#498,#499,#500,#501,#502,#503,#504,#505,#506,#507,#508,#509),.UNSPECIFIED.,.F.,.F.,(4,2,2,2,2,2,
2,2,2,2,2,2,2,2,2,2,2,2,2,2,4),(0.,16.140133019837,32.284779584,48.4328491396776,
64.5832812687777,80.7350703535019,96.8872940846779,112.998562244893,129.109127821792,
145.218618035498,161.326864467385,177.433985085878,193.540501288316,199.025994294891,
204.511471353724,209.996921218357,215.482344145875,220.970827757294,226.459331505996,
231.947902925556,237.436608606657),.UNSPECIFIED.);
#511=CARTESIAN_POINT('',(236.728,-73.152,-50.0159218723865));
#512=VERTEX_POINT('',#511);
#513=EDGE_CURVE('E137',#465,#512,#510,.T.);
#514=ORIENTED_EDGE('',*,*,#513,.T.);
#515=CARTESIAN_POINT('',(236.728,-73.152,-50.0159218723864));
#516=CARTESIAN_POINT('',(236.838793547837,-73.1461848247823,-50.0077539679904));
#517=CARTESIAN_POINT('',(236.94958602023,-73.1403697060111,-49.9995714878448));
#518=CARTESIAN_POINT('',(237.171168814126,-73.1287395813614,-49.9831773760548));
#519=CARTESIAN_POINT('',(237.28195913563,-73.122924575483,-49.9749657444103));
#520=CARTESIAN_POINT('',(237.39274838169,-73.1171096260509,-49.9667395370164));
#521=B_SPLINE_CURVE_WITH_KNOTS('',3,(#515,#516,#517,#518,#519,#520),.UNSPECIFIED.,.F.,.F.,(4,2,
4),(0.,0.333738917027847,0.667477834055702),.UNSPECIFIED.);
#522=CARTESIAN_POINT('',(237.39274838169,-73.1171096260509,-49.9667395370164));
#523=VERTEX_POINT('',#522);
#524=EDGE_CURVE('E74',#512,#523,#521,.T.);
#525=ORIENTED_EDGE('',*,*,#524,.T.);
#526=CARTESIAN_POINT('',(237.39274838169,-73.1171096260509,-49.9667395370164));
#527=CARTESIAN_POINT('',(240.775495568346,-72.7137305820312,-50.0459976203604));
#528=CARTESIAN_POINT('',(244.158606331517,-72.3103081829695,-50.1094084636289));
#529=CARTESIAN_POINT('',(250.923759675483,-71.503590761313,-50.2047467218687));
#530=CARTESIAN_POINT('',(254.30580206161,-71.1002957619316,-50.2366881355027));
#531=CARTESIAN_POINT('',(261.068818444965,-70.2938331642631,-50.2693628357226));
#532=CARTESIAN_POINT('',(264.449792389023,-69.8906655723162,-50.2701073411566));
#533=CARTESIAN_POINT('',(271.210673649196,-69.0844575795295,-50.2404459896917));
#534=CARTESIAN_POINT('',(274.590581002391,-68.6814171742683,-50.2100487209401));
#535=CARTESIAN_POINT('',(281.349329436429,-67.8754635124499,-50.1180025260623));
#536=CARTESIAN_POINT('',(284.728170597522,-67.4725502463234,-50.0563595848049));
#537=CARTESIAN_POINT('',(291.484786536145,-66.6668508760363,-49.9015434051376));
#538=CARTESIAN_POINT('',(294.862561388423,-66.2640647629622,-49.8083734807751));
#539=CARTESIAN_POINT('',(301.617258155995,-65.4585942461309,-49.5900364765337));
#540=CARTESIAN_POINT('',(304.994180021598,-65.0559098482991,-49.4648678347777));
#541=CARTESIAN_POINT('',(311.746951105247,-64.2506689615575,-49.1818803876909));
#542=CARTESIAN_POINT('',(315.122800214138,-63.848112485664,-49.0240589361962));
#543=CARTESIAN_POINT('',(321.873374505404,-63.0431335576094,-48.6748969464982));
#544=CARTESIAN_POINT('',(325.248099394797,-62.6407111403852,-48.4835506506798));
#545=CARTESIAN_POINT('',(331.996356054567,-61.8360085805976,-48.0662288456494));
#546=CARTESIAN_POINT('',(335.369887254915,-61.4337285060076,-47.8402439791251));
#547=CARTESIAN_POINT('',(342.115683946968,-60.6293192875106,-47.3522586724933));
#548=CARTESIAN_POINT('',(345.487948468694,-60.2271902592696,-47.0902445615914));
#549=CARTESIAN_POINT('',(350.544869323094,-59.6241727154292,-46.6689569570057));
#550=CARTESIAN_POINT('',(352.230691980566,-59.4231451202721,-46.5237761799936));
#551=CARTESIAN_POINT('',(355.601493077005,-59.0211905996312,-46.2237586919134));
#552=CARTESIAN_POINT('',(357.286471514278,-58.8202636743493,-46.0689219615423));
#553=CARTESIAN_POINT('',(358.97099166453,-58.6193913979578,-45.9091335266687));
#554=B_SPLINE_CURVE_WITH_KNOTS('',3,(#526,#527,#528,#529,#530,#531,#532,#533,#534,#535,#536,
#537,#538,#539,#540,#541,#542,#543,#544,#545,#546,#547,#548,#549,#550,#551,#552,#553),
.UNSPECIFIED.,.F.,.F.,(4,2,2,2,2,2,2,2,2,2,2,2,2,4),(0.,10.2228637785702,20.4411780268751,
30.6558175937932,40.867640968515,51.0775090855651,61.2863042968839,71.49559790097,
81.705719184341,91.9175956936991,102.132235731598,112.350762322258,117.462625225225,
122.574498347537),.UNSPECIFIED.);
#555=CARTESIAN_POINT('',(358.97099166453,-58.6193913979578,-45.9091335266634));
#556=VERTEX_POINT('',#555);
#557=EDGE_CURVE('E259',#523,#556,#554,.T.);
#558=ORIENTED_EDGE('',*,*,#557,.T.);
#559=CARTESIAN_POINT('',(358.97099166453,-58.6193913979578,-45.9091335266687));
#560=CARTESIAN_POINT('',(359.190953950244,-58.5659361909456,-45.9230310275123));
#561=CARTESIAN_POINT('',(359.410924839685,-58.5124788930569,-45.9367811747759));
#562=CARTESIAN_POINT('',(359.850883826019,-58.4055601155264,-45.9639867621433));
#563=CARTESIAN_POINT('',(360.070871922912,-58.3520986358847,-45.977442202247));
#564=CARTESIAN_POINT('',(360.290868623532,-58.2986350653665,-45.9907502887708));
#565=B_SPLINE_CURVE_WITH_KNOTS('',3,(#559,#560,#561,#562,#563,#564),.UNSPECIFIED.,.F.,.F.,(4,2,
4),(0.,0.680371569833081,1.36074313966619),.UNSPECIFIED.);
#566=CARTESIAN_POINT('',(360.290868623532,-58.2986350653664,-45.990750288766));
#567=VERTEX_POINT('',#566);
#568=EDGE_CURVE('E252',#556,#567,#565,.T.);
#569=ORIENTED_EDGE('',*,*,#568,.T.);
#570=CARTESIAN_POINT('',(360.290868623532,-58.2986350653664,-45.9907502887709));
#571=CARTESIAN_POINT('',(361.133896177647,-57.9951451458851,-46.1667539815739));
#572=CARTESIAN_POINT('',(361.977756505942,-57.6913554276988,-46.3382111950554));
#573=CARTESIAN_POINT('',(363.667025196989,-57.0832186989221,-46.6722534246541));
#574=CARTESIAN_POINT('',(364.512433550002,-56.7788716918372,-46.8348384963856));
#575=CARTESIAN_POINT('',(367.048311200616,-55.8659557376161,-47.3091505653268));
#576=CARTESIAN_POINT('',(368.740933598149,-55.2566116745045,-47.6079549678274));
#577=CARTESIAN_POINT('',(372.129162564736,-54.0368492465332,-48.1722574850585));
#578=CARTESIAN_POINT('',(373.82476382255,-53.4264327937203,-48.4377917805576));
#579=CARTESIAN_POINT('',(377.218777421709,-52.2045878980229,-48.9370138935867));
#580=CARTESIAN_POINT('',(378.917186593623,-51.593160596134,-49.1707260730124));
#581=CARTESIAN_POINT('',(382.31665607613,-50.3693515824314,-49.6075082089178));
#582=CARTESIAN_POINT('',(384.017714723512,-49.756970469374,-49.8105928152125));
#583=CARTESIAN_POINT('',(387.422356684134,-48.5312993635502,-50.187107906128));
#584=CARTESIAN_POINT('',(389.125939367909,-47.9180095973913,-50.3605448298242));
#585=CARTESIAN_POINT('',(392.535150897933,-46.6906934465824,-50.6785292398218));
#586=CARTESIAN_POINT('',(394.240779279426,-46.0766672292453,-50.8230823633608));
#587=CARTESIAN_POINT('',(397.654479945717,-44.8477349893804,-51.0839870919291));
#588=CARTESIAN_POINT('',(399.362552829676,-44.2328287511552,-51.2003298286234));
#589=CARTESIAN_POINT('',(402.781125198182,-43.0021426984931,-51.4052932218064));
#590=CARTESIAN_POINT('',(404.491625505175,-42.3863625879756,-51.4938983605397));
#591=CARTESIAN_POINT('',(407.91504113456,-41.1539329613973,-51.6437214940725));
#592=CARTESIAN_POINT('',(409.627957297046,-40.5372831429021,-51.7049177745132));
#593=CARTESIAN_POINT('',(413.056197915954,-39.3031165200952,-51.8001317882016));
#594=CARTESIAN_POINT('',(414.77152305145,-38.685599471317,-51.8341218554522));
#595=CARTESIAN_POINT('',(418.204581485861,-37.4496984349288,-51.8749764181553));
#596=CARTESIAN_POINT('',(419.922315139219,-36.8313143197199,-51.8818073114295));
#597=CARTESIAN_POINT('',(421.64,-36.2129477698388,-51.8750951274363));
#598=B_SPLINE_CURVE_WITH_KNOTS('',3,(#570,#571,#572,#573,#574,#575,#576,#577,#578,#579,#580,
#581,#582,#583,#584,#585,#586,#587,#588,#589,#590,#591,#592,#593,#594,#595,#596,#597),
.UNSPECIFIED.,.F.,.F.,(4,2,2,2,2,2,2,2,2,2,2,2,2,4),(0.,2.73931878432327,5.47862039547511,
10.9491006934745,16.4135793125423,21.873850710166,27.3315020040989,32.7879664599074,
38.2433649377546,43.7004761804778,49.1606349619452,54.6251118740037,60.0951385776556,
65.5719308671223),.UNSPECIFIED.);
#599=CARTESIAN_POINT('',(421.64,-36.2129477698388,-51.8750951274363));
#600=VERTEX_POINT('',#599);
#601=EDGE_CURVE('E245',#567,#600,#598,.T.);
#602=ORIENTED_EDGE('',*,*,#601,.T.);
#603=CARTESIAN_POINT('',(421.64,0.,0.));
#604=DIRECTION('',(-1.,0.,0.));
#605=DIRECTION('',(0.,0.,1.));
#606=AXIS2_PLACEMENT_3D('',#603,#604,#605);
#607=CIRCLE('',#606,63.2645483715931);
#608=CARTESIAN_POINT('',(421.64,36.2129477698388,-51.8750951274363));
#609=VERTEX_POINT('',#608);
#610=EDGE_CURVE('E207',#600,#609,#607,.F.);
#611=ORIENTED_EDGE('',*,*,#610,.T.);
#612=CARTESIAN_POINT('',(421.64,36.2129477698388,-51.8750951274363));
#613=CARTESIAN_POINT('',(419.922315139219,36.83131431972,-51.8818073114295));
#614=CARTESIAN_POINT('',(418.204581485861,37.4496984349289,-51.8749764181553));
#615=CARTESIAN_POINT('',(414.77152305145,38.685599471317,-51.8341218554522));
#616=CARTESIAN_POINT('',(413.056197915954,39.3031165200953,-51.8001317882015));
#617=CARTESIAN_POINT('',(409.627957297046,40.5372831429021,-51.7049177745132));
#618=CARTESIAN_POINT('',(407.91504113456,41.1539329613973,-51.6437214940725));
#619=CARTESIAN_POINT('',(404.491625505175,42.3863625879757,-51.4938983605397));
#620=CARTESIAN_POINT('',(402.781125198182,43.0021426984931,-51.4052932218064));
#621=CARTESIAN_POINT('',(399.362552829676,44.2328287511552,-51.2003298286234));
#622=CARTESIAN_POINT('',(397.654479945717,44.8477349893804,-51.0839870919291));
#623=CARTESIAN_POINT('',(394.240779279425,46.0766672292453,-50.8230823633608));
#624=CARTESIAN_POINT('',(392.535150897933,46.6906934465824,-50.6785292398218));
#625=CARTESIAN_POINT('',(389.125939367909,47.9180095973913,-50.3605448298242));
#626=CARTESIAN_POINT('',(387.422356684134,48.5312993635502,-50.187107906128));
#627=CARTESIAN_POINT('',(384.017714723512,49.756970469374,-49.8105928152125));
#628=CARTESIAN_POINT('',(382.31665607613,50.3693515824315,-49.6075082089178));
#629=CARTESIAN_POINT('',(378.917186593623,51.593160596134,-49.1707260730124));
#630=CARTESIAN_POINT('',(377.218777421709,52.2045878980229,-48.9370138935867));
#631=CARTESIAN_POINT('',(373.824763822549,53.4264327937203,-48.4377917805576));
#632=CARTESIAN_POINT('',(372.129162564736,54.0368492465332,-48.1722574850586));
#633=CARTESIAN_POINT('',(368.740933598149,55.2566116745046,-47.6079549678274));
#634=CARTESIAN_POINT('',(367.048311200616,55.8659557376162,-47.3091505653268));
#635=CARTESIAN_POINT('',(364.512433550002,56.7788716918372,-46.8348384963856));
#636=CARTESIAN_POINT('',(363.667025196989,57.0832186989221,-46.6722534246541));
#637=CARTESIAN_POINT('',(361.977756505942,57.6913554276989,-46.3382111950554));
#638=CARTESIAN_POINT('',(361.133896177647,57.9951451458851,-46.1667539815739));
#639=CARTESIAN_POINT('',(360.290868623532,58.2986350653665,-45.9907502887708));
#640=B_SPLINE_CURVE_WITH_KNOTS('',3,(#612,#613,#614,#615,#616,#617,#618,#619,#620,#621,#622,
#623,#624,#625,#626,#627,#628,#629,#630,#631,#632,#633,#634,#635,#636,#637,#638,#639),
.UNSPECIFIED.,.F.,.F.,(4,2,2,2,2,2,2,2,2,2,2,2,2,4),(0.,5.4767922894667,10.9468189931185,
16.4112959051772,21.8714546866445,27.3285659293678,32.783964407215,38.2404288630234,
43.6980801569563,49.1583515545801,54.6228301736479,60.0933104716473,62.8326120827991,
65.5719308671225),.UNSPECIFIED.);
#641=CARTESIAN_POINT('',(360.290868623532,58.2986350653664,-45.990750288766));
#642=VERTEX_POINT('',#641);
#643=EDGE_CURVE('E238',#609,#642,#640,.T.);
#644=ORIENTED_EDGE('',*,*,#643,.T.);
#645=CARTESIAN_POINT('',(360.290868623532,58.2986350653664,-45.9907502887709));
#646=CARTESIAN_POINT('',(360.070871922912,58.3520986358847,-45.977442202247));
#647=CARTESIAN_POINT('',(359.850883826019,58.4055601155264,-45.9639867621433));
#648=CARTESIAN_POINT('',(359.410924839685,58.5124788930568,-45.9367811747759));
#649=CARTESIAN_POINT('',(359.190953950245,58.5659361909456,-45.9230310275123));
#650=CARTESIAN_POINT('',(358.97099166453,58.6193913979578,-45.9091335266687));
#651=B_SPLINE_CURVE_WITH_KNOTS('',3,(#645,#646,#647,#648,#649,#650),.UNSPECIFIED.,.F.,.F.,(4,2,
4),(0.,0.680371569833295,1.36074313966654),.UNSPECIFIED.);
#652=CARTESIAN_POINT('',(358.97099166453,58.6193913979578,-45.9091335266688));
#653=VERTEX_POINT('',#652);
#654=EDGE_CURVE('E231',#642,#653,#651,.T.);
#655=ORIENTED_EDGE('',*,*,#654,.T.);
#656=CARTESIAN_POINT('',(358.97099166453,58.6193913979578,-45.9091335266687));
#657=CARTESIAN_POINT('',(357.286471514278,58.8202636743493,-46.0689219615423));
#658=CARTESIAN_POINT('',(355.601493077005,59.0211905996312,-46.2237586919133));
#659=CARTESIAN_POINT('',(352.230691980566,59.4231451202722,-46.5237761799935));
#660=CARTESIAN_POINT('',(350.544869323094,59.6241727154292,-46.6689569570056));
#661=CARTESIAN_POINT('',(345.487948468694,60.2271902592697,-47.0902445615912));
#662=CARTESIAN_POINT('',(342.115683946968,60.6293192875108,-47.3522586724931));
#663=CARTESIAN_POINT('',(335.369887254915,61.4337285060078,-47.8402439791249));
#664=CARTESIAN_POINT('',(331.996356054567,61.8360085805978,-48.0662288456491));
#665=CARTESIAN_POINT('',(325.248099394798,62.6407111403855,-48.4835506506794));
#666=CARTESIAN_POINT('',(321.873374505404,63.0431335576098,-48.6748969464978));
#667=CARTESIAN_POINT('',(315.122800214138,63.8481124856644,-49.0240589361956));
#668=CARTESIAN_POINT('',(311.746951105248,64.2506689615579,-49.1818803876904));
#669=CARTESIAN_POINT('',(304.994180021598,65.0559098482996,-49.4648678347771));
#670=CARTESIAN_POINT('',(301.617258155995,65.4585942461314,-49.590036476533));
#671=CARTESIAN_POINT('',(294.862561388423,66.2640647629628,-49.8083734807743));
#672=CARTESIAN_POINT('',(291.484786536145,66.6668508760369,-49.9015434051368));
#673=CARTESIAN_POINT('',(284.728170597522,67.472550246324,-50.056359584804));
#674=CARTESIAN_POINT('',(281.349329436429,67.8754635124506,-50.1180025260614));
#675=CARTESIAN_POINT('',(274.590581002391,68.681417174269,-50.2100487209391));
#676=CARTESIAN_POINT('',(271.210673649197,69.0844575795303,-50.2404459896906));
#677=CARTESIAN_POINT('',(264.449792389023,69.890665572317,-50.2701073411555));
#678=CARTESIAN_POINT('',(261.068818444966,70.2938331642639,-50.2693628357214));
#679=CARTESIAN_POINT('',(254.30580206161,71.1002957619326,-50.2366881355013));
#680=CARTESIAN_POINT('',(250.923759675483,71.503590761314,-50.2047467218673));
#681=CARTESIAN_POINT('',(244.158606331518,72.3103081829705,-50.1094084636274));
#682=CARTESIAN_POINT('',(240.775495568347,72.7137305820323,-50.0459976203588));
#683=CARTESIAN_POINT('',(237.39274838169,73.117109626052,-49.9667395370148));
#684=B_SPLINE_CURVE_WITH_KNOTS('',3,(#656,#657,#658,#659,#660,#661,#662,#663,#664,#665,#666,
#667,#668,#669,#670,#671,#672,#673,#674,#675,#676,#677,#678,#679,#680,#681,#682,#683),
.UNSPECIFIED.,.F.,.F.,(4,2,2,2,2,2,2,2,2,2,2,2,2,4),(0.,5.11187312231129,10.2237360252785,
20.4422626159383,30.6569026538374,40.8687791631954,51.0789004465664,61.2881940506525,
71.4969892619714,81.7068573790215,91.9186807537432,102.133320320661,112.351634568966,
122.574498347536),.UNSPECIFIED.);
#685=EDGE_CURVE('E224',#653,#403,#684,.T.);
#686=ORIENTED_EDGE('',*,*,#685,.T.);
#687=EDGE_LOOP('',(#407,#458,#467,#514,#525,#558,#569,#602,#611,#644,#655,#686));
#688=FACE_BOUND('',#687,.T.);
#689=ADVANCED_FACE('F208',(#688),#394,.F.);
#690=CARTESIAN_POINT('',(-9.906,0.,0.));
#691=DIRECTION('',(1.,0.,0.));
#692=DIRECTION('',(0.,0.,-1.));
#693=AXIS2_PLACEMENT_3D('',#690,#691,#692);
#694=CYLINDRICAL_SURFACE('',#693,98.171);
#695=ORIENTED_EDGE('',*,*,#466,.F.);
#696=DIRECTION('',(1.,0.,0.));
#697=VECTOR('',#696,1.);
#698=CARTESIAN_POINT('',(-9.906,73.152,-65.4700705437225));
#699=LINE('',#698,#697);
#700=EDGE_CURVE('E141',#456,#363,#699,.F.);
#701=ORIENTED_EDGE('',*,*,#700,.T.);
#702=ORIENTED_EDGE('',*,*,#366,.T.);
#703=DIRECTION('',(1.,0.,0.));
#704=VECTOR('',#703,1.);
#705=CARTESIAN_POINT('',(-9.906,-73.152,-65.4700705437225));
#706=LINE('',#705,#704);
#707=EDGE_CURVE('E140',#365,#465,#706,.T.);
#708=ORIENTED_EDGE('',*,*,#707,.T.);
#709=EDGE_LOOP('',(#695,#701,#702,#708));
#710=FACE_BOUND('',#709,.T.);
#711=ADVANCED_FACE('F213',(#710),#694,.F.);
#712=CARTESIAN_POINT('',(236.728,73.1520000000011,-101.346));
#713=DIRECTION('',(0.0524144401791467,0.998625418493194,0.));
#714=DIRECTION('',(-0.998625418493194,0.0524144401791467,0.));
#715=AXIS2_PLACEMENT_3D('',#712,#713,#714);
#716=PLANE('',#715);
#717=ORIENTED_EDGE('',*,*,#91,.T.);
#718=DIRECTION('',(0.,0.,1.));
#719=VECTOR('',#718,1.);
#720=CARTESIAN_POINT('',(236.728,73.1520000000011,-101.346));
#721=LINE('',#720,#719);
#722=EDGE_CURVE('E147',#77,#405,#721,.T.);
#723=ORIENTED_EDGE('',*,*,#722,.T.);
#724=ORIENTED_EDGE('',*,*,#406,.F.);
#725=DIRECTION('',(0.,0.,1.));
#726=VECTOR('',#725,1.);
#727=CARTESIAN_POINT('',(237.39274838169,73.117109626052,-101.346));
#728=LINE('',#727,#726);
#729=EDGE_CURVE('E152',#90,#403,#728,.T.);
#730=ORIENTED_EDGE('',*,*,#729,.F.);
#731=EDGE_LOOP('',(#717,#723,#724,#730));
#732=FACE_BOUND('',#731,.T.);
#733=ADVANCED_FACE('F279',(#732),#716,.T.);
#734=CARTESIAN_POINT('',(237.39274838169,73.117109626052,-101.346));
#735=DIRECTION('',(0.118407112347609,0.992965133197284,0.));
#736=DIRECTION('',(-0.992965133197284,0.118407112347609,0.));
#737=AXIS2_PLACEMENT_3D('',#734,#735,#736);
#738=PLANE('',#737);
#739=ORIENTED_EDGE('',*,*,#124,.T.);
#740=ORIENTED_EDGE('',*,*,#729,.T.);
#741=ORIENTED_EDGE('',*,*,#685,.F.);
#742=DIRECTION('',(0.,0.,1.));
#743=VECTOR('',#742,1.);
#744=CARTESIAN_POINT('',(358.97099166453,58.6193913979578,-101.346));
#745=LINE('',#744,#743);
#746=EDGE_CURVE('E156',#123,#653,#745,.T.);
#747=ORIENTED_EDGE('',*,*,#746,.F.);
#748=EDGE_LOOP('',(#739,#740,#741,#747));
#749=FACE_BOUND('',#748,.T.);
#750=ADVANCED_FACE('F282',(#749),#738,.T.);
#751=CARTESIAN_POINT('',(358.97099166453,58.6193913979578,-101.346));
#752=DIRECTION('',(0.236146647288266,0.971717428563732,0.));
#753=DIRECTION('',(-0.971717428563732,0.236146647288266,0.));
#754=AXIS2_PLACEMENT_3D('',#751,#752,#753);
#755=PLANE('',#754);
#756=ORIENTED_EDGE('',*,*,#135,.T.);
#757=ORIENTED_EDGE('',*,*,#746,.T.);
#758=ORIENTED_EDGE('',*,*,#654,.F.);
#759=DIRECTION('',(0.,0.,1.));
#760=VECTOR('',#759,1.);
#761=CARTESIAN_POINT('',(360.290868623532,58.2986350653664,-101.346));
#762=LINE('',#761,#760);
#763=EDGE_CURVE('E145',#134,#642,#762,.T.);
#764=ORIENTED_EDGE('',*,*,#763,.F.);
#765=EDGE_LOOP('',(#756,#757,#758,#764));
#766=FACE_BOUND('',#765,.T.);
#767=ADVANCED_FACE('F339',(#766),#755,.T.);
#768=CARTESIAN_POINT('',(421.64,36.2129477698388,-101.346));
#769=DIRECTION('',(0.338719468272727,0.940887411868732,0.));
#770=DIRECTION('',(-0.940887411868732,0.338719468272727,0.));
#771=AXIS2_PLACEMENT_3D('',#768,#769,#770);
#772=PLANE('',#771);
#773=ORIENTED_EDGE('',*,*,#166,.T.);
#774=ORIENTED_EDGE('',*,*,#763,.T.);
#775=ORIENTED_EDGE('',*,*,#643,.F.);
#776=DIRECTION('',(0.,0.,1.));
#777=VECTOR('',#776,1.);
#778=CARTESIAN_POINT('',(421.64,36.2129477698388,-101.346));
#779=LINE('',#778,#777);
#780=EDGE_CURVE('E144',#165,#609,#779,.T.);
#781=ORIENTED_EDGE('',*,*,#780,.F.);
#782=EDGE_LOOP('',(#773,#774,#775,#781));
#783=FACE_BOUND('',#782,.T.);
#784=ADVANCED_FACE('F336',(#783),#772,.T.);
#785=CARTESIAN_POINT('',(421.64,-36.2129477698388,-101.346));
#786=DIRECTION('',(1.,0.,0.));
#787=DIRECTION('',(0.,0.,-1.));
#788=AXIS2_PLACEMENT_3D('',#785,#786,#787);
#789=PLANE('',#788);
#790=ORIENTED_EDGE('',*,*,#175,.T.);
#791=ORIENTED_EDGE('',*,*,#780,.T.);
#792=ORIENTED_EDGE('',*,*,#610,.F.);
#793=DIRECTION('',(0.,0.,1.));
#794=VECTOR('',#793,1.);
#795=CARTESIAN_POINT('',(421.64,-36.2129477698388,-101.346));
#796=LINE('',#795,#794);
#797=EDGE_CURVE('E165',#174,#600,#796,.T.);
#798=ORIENTED_EDGE('',*,*,#797,.F.);
#799=EDGE_LOOP('',(#790,#791,#792,#798));
#800=FACE_BOUND('',#799,.T.);
#801=ADVANCED_FACE('F321',(#800),#789,.T.);
#802=CARTESIAN_POINT('',(421.64,-36.2129477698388,-101.346));
#803=DIRECTION('',(0.338719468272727,-0.940887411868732,0.));
#804=DIRECTION('',(0.940887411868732,0.338719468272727,0.));
#805=AXIS2_PLACEMENT_3D('',#802,#803,#804);
#806=PLANE('',#805);
#807=ORIENTED_EDGE('',*,*,#206,.T.);
#808=ORIENTED_EDGE('',*,*,#797,.T.);
#809=ORIENTED_EDGE('',*,*,#601,.F.);
#810=DIRECTION('',(0.,0.,1.));
#811=VECTOR('',#810,1.);
#812=CARTESIAN_POINT('',(360.290868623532,-58.2986350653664,-101.346));
#813=LINE('',#812,#811);
#814=EDGE_CURVE('E169',#205,#567,#813,.T.);
#815=ORIENTED_EDGE('',*,*,#814,.F.);
#816=EDGE_LOOP('',(#807,#808,#809,#815));
#817=FACE_BOUND('',#816,.T.);
#818=ADVANCED_FACE('F315',(#817),#806,.T.);
#819=CARTESIAN_POINT('',(358.97099166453,-58.6193913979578,-101.346));
#820=DIRECTION('',(0.236146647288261,-0.971717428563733,0.));
#821=DIRECTION('',(0.971717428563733,0.236146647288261,0.));
#822=AXIS2_PLACEMENT_3D('',#819,#820,#821);
#823=PLANE('',#822);
#824=ORIENTED_EDGE('',*,*,#217,.T.);
#825=ORIENTED_EDGE('',*,*,#814,.T.);
#826=ORIENTED_EDGE('',*,*,#568,.F.);
#827=DIRECTION('',(0.,0.,1.));
#828=VECTOR('',#827,1.);
#829=CARTESIAN_POINT('',(358.97099166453,-58.6193913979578,-101.346));
#830=LINE('',#829,#828);
#831=EDGE_CURVE('E173',#216,#556,#830,.T.);
#832=ORIENTED_EDGE('',*,*,#831,.F.);
#833=EDGE_LOOP('',(#824,#825,#826,#832));
#834=FACE_BOUND('',#833,.T.);
#835=ADVANCED_FACE('F310',(#834),#823,.T.);
#836=CARTESIAN_POINT('',(237.39274838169,-73.1171096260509,-101.346));
#837=DIRECTION('',(0.1184071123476,-0.992965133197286,0.));
#838=DIRECTION('',(0.992965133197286,0.1184071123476,0.));
#839=AXIS2_PLACEMENT_3D('',#836,#837,#838);
#840=PLANE('',#839);
#841=ORIENTED_EDGE('',*,*,#250,.T.);
#842=ORIENTED_EDGE('',*,*,#831,.T.);
#843=ORIENTED_EDGE('',*,*,#557,.F.);
#844=DIRECTION('',(0.,0.,1.));
#845=VECTOR('',#844,1.);
#846=CARTESIAN_POINT('',(237.39274838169,-73.1171096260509,-101.346));
#847=LINE('',#846,#845);
#848=EDGE_CURVE('E176',#249,#523,#847,.T.);
#849=ORIENTED_EDGE('',*,*,#848,.F.);
#850=EDGE_LOOP('',(#841,#842,#843,#849));
#851=FACE_BOUND('',#850,.T.);
#852=ADVANCED_FACE('F307',(#851),#840,.T.);
#853=CARTESIAN_POINT('',(236.728,-73.152,-101.346));
#854=DIRECTION('',(0.0524144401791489,-0.998625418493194,0.));
#855=DIRECTION('',(0.998625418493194,0.0524144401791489,0.));
#856=AXIS2_PLACEMENT_3D('',#853,#854,#855);
#857=PLANE('',#856);
#858=ORIENTED_EDGE('',*,*,#261,.T.);
#859=ORIENTED_EDGE('',*,*,#848,.T.);
#860=ORIENTED_EDGE('',*,*,#524,.F.);
#861=DIRECTION('',(0.,0.,1.));
#862=VECTOR('',#861,1.);
#863=CARTESIAN_POINT('',(236.728,-73.152,-101.346));
#864=LINE('',#863,#862);
#865=EDGE_CURVE('E48',#260,#512,#864,.T.);
#866=ORIENTED_EDGE('',*,*,#865,.F.);
#867=EDGE_LOOP('',(#858,#859,#860,#866));
#868=FACE_BOUND('',#867,.T.);
#869=ADVANCED_FACE('F200',(#868),#857,.T.);
#870=CARTESIAN_POINT('',(0.,73.152,-101.346));
#871=DIRECTION('',(0.,1.,0.));
#872=DIRECTION('',(0.,0.,1.));
#873=AXIS2_PLACEMENT_3D('',#870,#871,#872);
#874=PLANE('',#873);
#875=ORIENTED_EDGE('',*,*,#80,.T.);
#876=ORIENTED_EDGE('',*,*,#331,.T.);
#877=ORIENTED_EDGE('',*,*,#372,.T.);
#878=ORIENTED_EDGE('',*,*,#700,.F.);
#879=ORIENTED_EDGE('',*,*,#457,.F.);
#880=ORIENTED_EDGE('',*,*,#722,.F.);
#881=EDGE_LOOP('',(#875,#876,#877,#878,#879,#880));
#882=FACE_BOUND('',#881,.T.);
#883=ADVANCED_FACE('F107',(#882),#874,.T.);
#884=CARTESIAN_POINT('',(236.728,-73.152,-101.346));
#885=DIRECTION('',(0.,-1.,0.));
#886=DIRECTION('',(0.,0.,-1.));
#887=AXIS2_PLACEMENT_3D('',#884,#885,#886);
#888=PLANE('',#887);
#889=ORIENTED_EDGE('',*,*,#308,.T.);
#890=ORIENTED_EDGE('',*,*,#865,.T.);
#891=ORIENTED_EDGE('',*,*,#513,.F.);
#892=ORIENTED_EDGE('',*,*,#707,.F.);
#893=ORIENTED_EDGE('',*,*,#379,.F.);
#894=ORIENTED_EDGE('',*,*,#340,.T.);
#895=EDGE_LOOP('',(#889,#890,#891,#892,#893,#894));
#896=FACE_BOUND('',#895,.T.);
#897=ADVANCED_FACE('F196',(#896),#888,.T.);
#898=CLOSED_SHELL('',(#319,#351,#383,#689,#711,#733,#750,#767,#784,#801,#818,#835,#852,#869,
#883,#897));
#899=MANIFOLD_SOLID_BREP('B2',#898);
#900=ADVANCED_BREP_SHAPE_REPRESENTATION('',(#18,#899),#14);
#901=SHAPE_DEFINITION_REPRESENTATION(#9,#900);
ENDSEC;
END-ISO-10303-21;
